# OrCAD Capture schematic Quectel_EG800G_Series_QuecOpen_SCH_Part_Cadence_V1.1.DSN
size A2

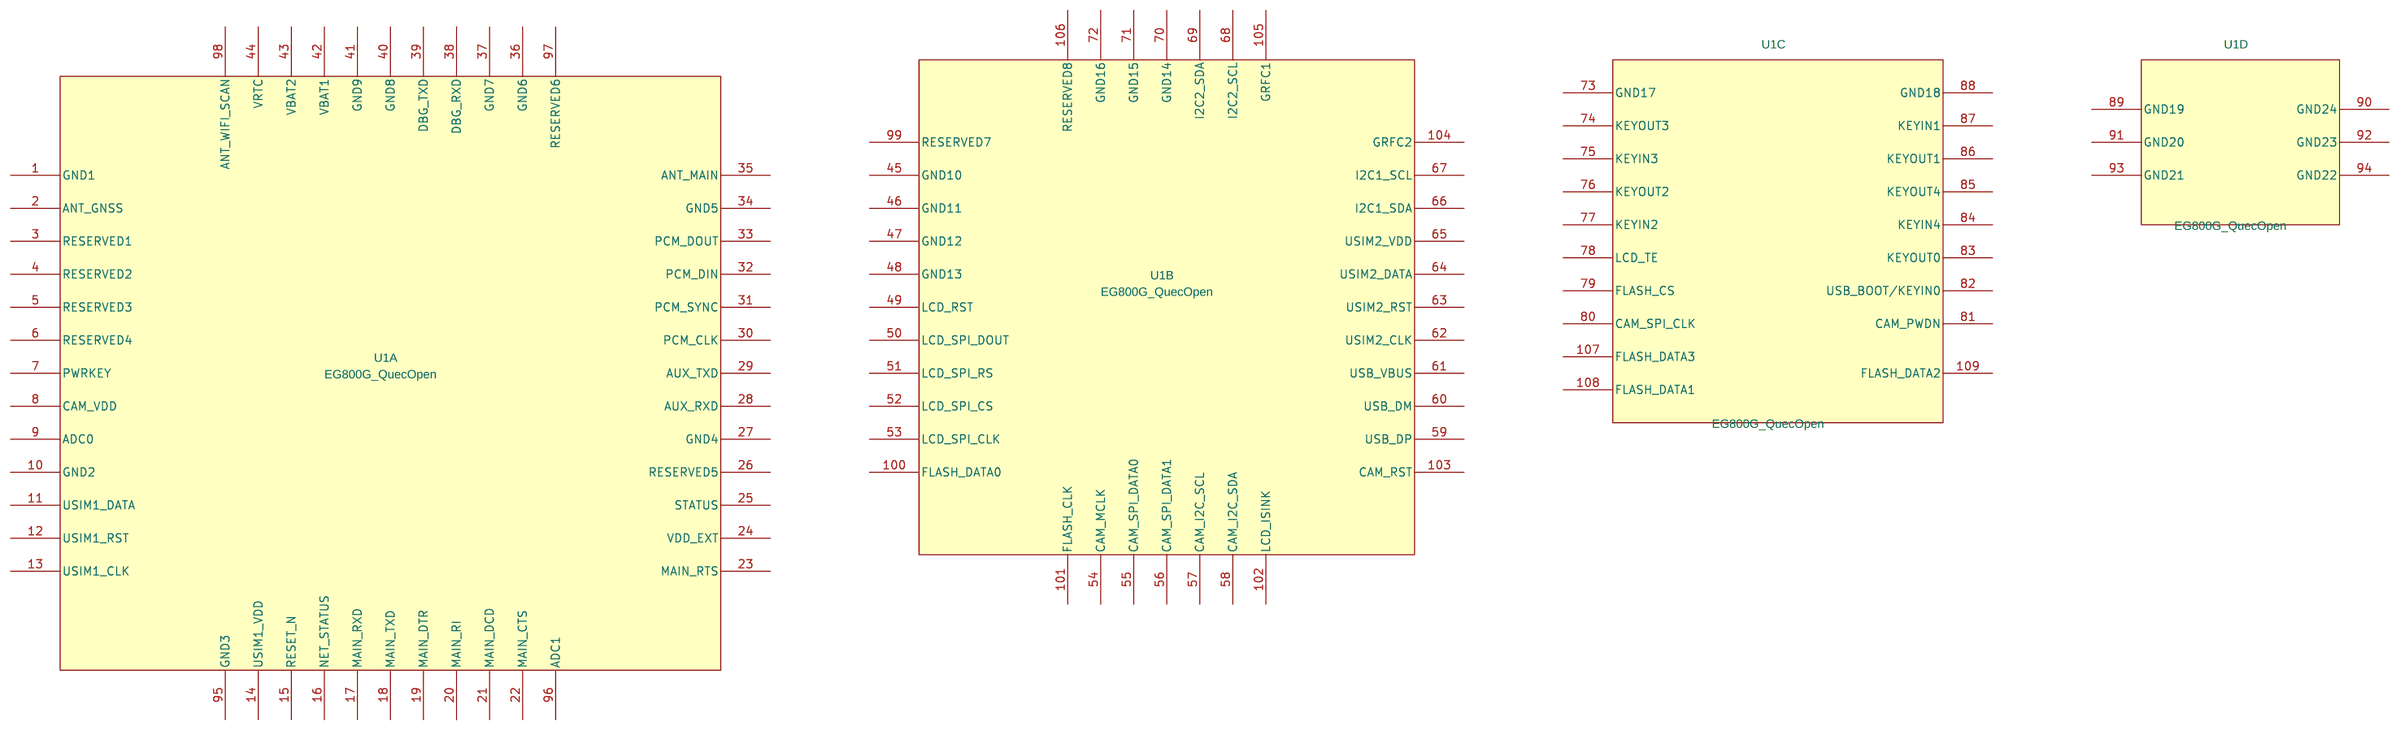
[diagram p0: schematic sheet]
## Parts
U1  EG800G_QuecOpen  [EG800G_QuecOpen]  (sections A,B,C,D)

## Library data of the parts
U1 = EG800G_QuecOpen

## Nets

Not connected (* = marked no-connect by the designer): U1 1(GND1) 2(ANT_GNSS) 3(RESERVED1) 4(RESERVED2) 5(RESERVED3) 6(RESERVED4) 7(PWRKEY) 8(CAM_VDD) 9(ADC0) 10(GND2) 11(USIM1_DATA) 12(USIM1_RST) 13(USIM1_CLK) 14(USIM1_VDD) 15(RESET_N) 16(NET_STATUS) 17(MAIN_RXD) 18(MAIN_TXD) 19(MAIN_DTR) 20(MAIN_RI) 21(MAIN_DCD) 22(MAIN_CTS) 23(MAIN_RTS) 24(VDD_EXT) 25(STATUS) 26(RESERVED5) 27(GND4) 28(AUX_RXD) 29(AUX_TXD) 30(PCM_CLK) 31(PCM_SYNC) 32(PCM_DIN) 33(PCM_DOUT) 34(GND5) 35(ANT_MAIN) 36(GND6) 37(GND7) 38(DBG_RXD) 39(DBG_TXD) 40(GND8) 41(GND9) 42(VBAT1) 43(VBAT2) 44(VRTC) 45(GND10) 46(GND11) 47(GND12) 48(GND13) 49(LCD_RST) 50(LCD_SPI_DOUT) 51(LCD_SPI_RS) 52(LCD_SPI_CS) 53(LCD_SPI_CLK) 54(CAM_MCLK) 55(CAM_SPI_DATA0) 56(CAM_SPI_DATA1) 57(CAM_I2C_SCL) 58(CAM_I2C_SDA) 59(USB_DP) 60(USB_DM) 61(USB_VBUS) 62(USIM2_CLK) 63(USIM2_RST) 64(USIM2_DATA) 65(USIM2_VDD) 66(I2C1_SDA) 67(I2C1_SCL) 68(I2C2_SCL) 69(I2C2_SDA) 70(GND14) 71(GND15) 72(GND16) 73(GND17) 74(KEYOUT3) 75(KEYIN3) 76(KEYOUT2) 77(KEYIN2) 78(LCD_TE) 79(FLASH_CS) 80(CAM_SPI_CLK) 81(CAM_PWDN) 82(USB_BOOT/KEYIN0) 83(KEYOUT0) 84(KEYIN4) 85(KEYOUT4) 86(KEYOUT1) 87(KEYIN1) 88(GND18) 89(GND19) 90(GND24) 91(GND20) 92(GND23) 93(GND21) 94(GND22) 95(GND3) 96(ADC1) 97(RESERVED6) 98(ANT_WIFI_SCAN) 99(RESERVED7) 100(FLASH_DATA0) 101(FLASH_CLK) 102(LCD_ISINK) 103(CAM_RST) 104(GRFC2) 105(GRFC1) 106(RESERVED8) 107(FLASH_DATA3) 108(FLASH_DATA1) 109(FLASH_DATA2)
